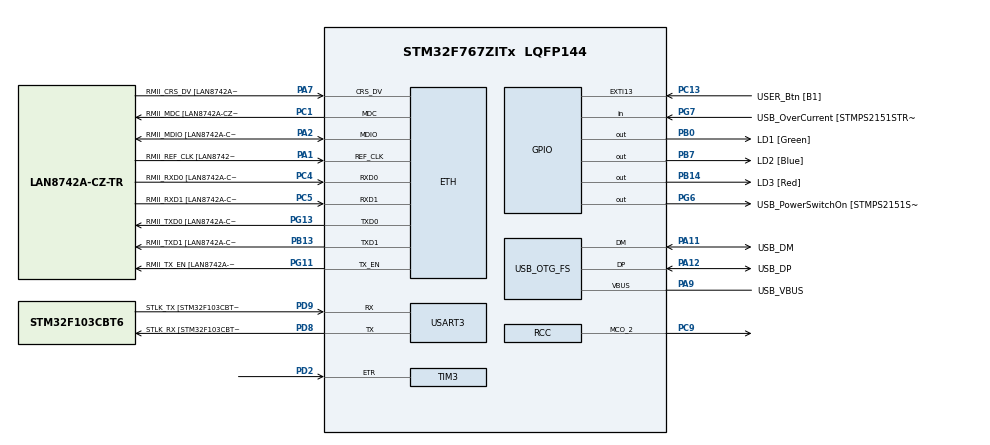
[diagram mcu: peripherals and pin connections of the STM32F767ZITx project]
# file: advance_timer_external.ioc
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ETH.MediaInterface=HAL_ETH_RMII_MODE
ETH.PHY_Name=LAN8742A_PHY_ADDRESS
ETH.PHY_Value=0
ETH.PhyAddress=0
Mcu.Family=STM32F7
Mcu.Name=STM32F767ZITx
Mcu.Package=LQFP144
NVIC.PriorityGroup=NVIC_PRIORITYGROUP_4
PA1.GPIO_Label=RMII_REF_CLK [LAN8742A-CZ-TR_REFCLK0]
PA1.Mode=RMII
PA1.Signal=ETH_REF_CLK
PA10.GPIO_Label=USB_ID
PA10.Signal=USB_OTG_FS_ID
PA11.GPIO_Label=USB_DM
PA11.Mode=Device_Only
PA11.Signal=USB_OTG_FS_DM
PA12.GPIO_Label=USB_DP
PA12.Mode=Device_Only
PA12.Signal=USB_OTG_FS_DP
PA13.GPIO_Label=TMS
PA13.Mode=Serial_Wire
PA13.Signal=SYS_JTMS-SWDIO
PA14.GPIO_Label=TCK
PA14.Mode=Serial_Wire
PA14.Signal=SYS_JTCK-SWCLK
PA2.GPIO_Label=RMII_MDIO [LAN8742A-CZ-TR_MDIO]
PA2.Mode=RMII
PA2.Signal=ETH_MDIO
PA7.GPIO_Label=RMII_CRS_DV [LAN8742A-CZ-TR_CRS_DV]
PA7.Mode=RMII
PA7.Signal=ETH_CRS_DV
PA9.GPIO_Label=USB_VBUS
PA9.Mode=Activate_VBUS
PA9.Signal=USB_OTG_FS_VBUS
PB0.GPIO_Label=LD1 [Green]
PB0.Signal=GPIO_Output
PB13.GPIO_Label=RMII_TXD1 [LAN8742A-CZ-TR_TXD1]
PB13.Mode=RMII
PB13.Signal=ETH_TXD1
PB14.GPIO_Label=LD3 [Red]
PB14.Signal=GPIO_Output
PB3.GPIO_Label=SWO
PB3.Signal=SYS_JTDO-SWO
PB7.GPIO_Label=LD2 [Blue]
PB7.Signal=GPIO_Output
PC1.GPIO_Label=RMII_MDC [LAN8742A-CZ-TR_MDC]
PC1.Mode=RMII
PC1.Signal=ETH_MDC
PC13.GPIO_Label=USER_Btn [B1]
PC13.Signal=GPXTI13
PC14/OSC32_IN.Signal=RCC_OSC32_IN
PC15/OSC32_OUT.Signal=RCC_OSC32_OUT
PC4.GPIO_Label=RMII_RXD0 [LAN8742A-CZ-TR_RXD0]
PC4.Mode=RMII
PC4.Signal=ETH_RXD0
PC5.GPIO_Label=RMII_RXD1 [LAN8742A-CZ-TR_RXD1]
PC5.Mode=RMII
PC5.Signal=ETH_RXD1
PC9.Mode=Clock-out-2
PC9.Signal=RCC_MCO_2
PD2.Signal=S_TIM3_ETR
PD8.GPIO_Label=STLK_RX [STM32F103CBT6_PA3]
PD8.Mode=Asynchronous
PD8.Signal=USART3_TX
PD9.GPIO_Label=STLK_TX [STM32F103CBT6_PA2]
PD9.Mode=Asynchronous
PD9.Signal=USART3_RX
PG11.GPIO_Label=RMII_TX_EN [LAN8742A-CZ-TR_TXEN]
PG11.Mode=RMII
PG11.Signal=ETH_TX_EN
PG13.GPIO_Label=RMII_TXD0 [LAN8742A-CZ-TR_TXD0]
PG13.Mode=RMII
PG13.Signal=ETH_TXD0
PG6.GPIO_Label=USB_PowerSwitchOn [STMPS2151STR_EN]
PG6.Signal=GPIO_Output
PG7.GPIO_Label=USB_OverCurrent [STMPS2151STR_FAULT]
PG7.Signal=GPIO_Input
PH0/OSC_IN.GPIO_Label=MCO [STM32F103CBT6_PA8]
PH0/OSC_IN.Mode=HSE-External-Oscillator
PH0/OSC_IN.Signal=RCC_OSC_IN
PH1/OSC_OUT.Mode=HSE-External-Oscillator
PH1/OSC_OUT.Signal=RCC_OSC_OUT
ProjectManager.HeapSize=0x200
ProjectManager.StackSize=0x400
ProjectManager.TargetToolchain=STM32CubeIDE
RCC.48MHZClocksFreq_Value=24000000
RCC.AHBFreq_Value=216000000
RCC.APB1CLKDivider=RCC_HCLK_DIV4
RCC.APB1Freq_Value=54000000
RCC.APB1TimFreq_Value=108000000
RCC.APB2CLKDivider=RCC_HCLK_DIV2
RCC.APB2Freq_Value=108000000
RCC.APB2TimFreq_Value=216000000
RCC.CortexFreq_Value=216000000
RCC.HCLKFreq_Value=216000000
RCC.HSE_VALUE=8000000
RCC.HSI_VALUE=16000000
RCC.LSE_VALUE=32768
RCC.PLLM=4
RCC.PLLMUL=RCC_PLL_MUL9
RCC.PLLN=216
RCC.PLLQ=9
RCC.PRESCALERUSB=RCC_USBCLKSOURCE_PLL_DIV1_5
RCC.SYSCLKFreq_VALUE=216000000
RCC.SYSCLKSource=RCC_SYSCLKSOURCE_PLLCLK
RCC.SYSCLKSourceVirtual=RCC_SYSCLKSOURCE_PLLCLK
RCC.USBFreq_Value=48000000
RCC.VCOOutputFreq_Value=432000000
SH.S_TIM3_ETR.0=TIM3_ETR,ClockSourceETR_Mode2
USART3.VirtualMode-Asynchronous=VM_ASYNC
USB_OTG_FS.VirtualMode=Device_Only
board=NUCLEO-F767ZI

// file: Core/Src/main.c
/* USER CODE BEGIN Header */
/**
  ******************************************************************************
  * @file           : main.c
  * @brief          : Main program body
  ******************************************************************************
  * @attention
  *
  * Copyright (c) 2026 STMicroelectronics.
  * All rights reserved.
  *
  * This software is licensed under terms that can be found in the LICENSE file
  * in the root directory of this software component.
  * If no LICENSE file comes with this software, it is provided AS-IS.
  *
  ******************************************************************************
  */
/* USER CODE END Header */
#include "main.h"
#include "string.h"

#if defined ( __ICCARM__ ) /*!< IAR Compiler */
#pragma location=0x2007c000
ETH_DMADescTypeDef  DMARxDscrTab[ETH_RX_DESC_CNT]; /* Ethernet Rx DMA Descriptors */
#pragma location=0x2007c0a0
ETH_DMADescTypeDef  DMATxDscrTab[ETH_TX_DESC_CNT]; /* Ethernet Tx DMA Descriptors */

#elif defined ( __CC_ARM )  /* MDK ARM Compiler */

__attribute__((at(0x2007c000))) ETH_DMADescTypeDef  DMARxDscrTab[ETH_RX_DESC_CNT]; /* Ethernet Rx DMA Descriptors */
__attribute__((at(0x2007c0a0))) ETH_DMADescTypeDef  DMATxDscrTab[ETH_TX_DESC_CNT]; /* Ethernet Tx DMA Descriptors */

#elif defined ( __GNUC__ ) /* GNU Compiler */

ETH_DMADescTypeDef DMARxDscrTab[ETH_RX_DESC_CNT] __attribute__((section(".RxDecripSection"))); /* Ethernet Rx DMA Descriptors */
ETH_DMADescTypeDef DMATxDscrTab[ETH_TX_DESC_CNT] __attribute__((section(".TxDecripSection")));   /* Ethernet Tx DMA Descriptors */
#endif

ETH_TxPacketConfig TxConfig;

ETH_HandleTypeDef heth;

TIM_HandleTypeDef htim3;

UART_HandleTypeDef huart3;

PCD_HandleTypeDef hpcd_USB_OTG_FS;

/* USER CODE BEGIN PV */

uint32_t frequency;
uint32_t countervalue1;
uint32_t countervalue2;

/* USER CODE END PV */

void SystemClock_Config(void);
static void MX_GPIO_Init(void);
static void MX_ETH_Init(void);
static void MX_USART3_UART_Init(void);
static void MX_USB_OTG_FS_PCD_Init(void);
static void MX_TIM3_Init(void);

/* USER CODE BEGIN 0 */

/* USER CODE BEGIN 0 */
uint32_t measuer_freq(void)
{
    static uint8_t state = 0;
    static uint32_t start_tick = 0;  // uint32_t yapıldı
    static uint32_t start_count = 0; // uint32_t yapıldı
    uint32_t freq = 0;

    if(state == 0)
    {
        start_tick = HAL_GetTick();
        start_count = __HAL_TIM_GET_COUNTER(&htim3); // __ eklendi
        state = 1;
    }
    else if(state == 1)
    {
        if((HAL_GetTick() - start_tick) >= 1000) // 1 saniye bekle
        {
            uint32_t end_count = __HAL_TIM_GET_COUNTER(&htim3); // __ eklendi

            // Timer taşmasını (overflow) hesaba katan fark alma
            if (end_count >= start_count) {
                freq = end_count - start_count;
                state = 0;
            }

        }
    }
    return freq;
}
/* USER CODE END 0 */

int main(void)
{

  /* MCU Configuration--------------------------------------------------------*/

  /* Reset of all peripherals, Initializes the Flash interface and the Systick. */
  HAL_Init();

  /* Configure the system clock */
  SystemClock_Config();

  /* Initialize all configured peripherals */
  MX_GPIO_Init();
  MX_ETH_Init();
  MX_USART3_UART_Init();
  MX_USB_OTG_FS_PCD_Init();
  MX_TIM3_Init();
  /* USER CODE BEGIN 2 */
  HAL_RCC_MCOConfig(RCC_MCO1, RCC_MCO1SOURCE_HSI, RCC_MCODIV_2);
  HAL_TIM_Base_Start(&htim3);

  /* USER CODE END 2 */

  /* Infinite loop */
  while (1)
  {

    /* USER CODE BEGIN 3 */
	  	 /* external clock mode
	countervalue1 =   __HAL_TIM_GET_COUNTER(&htim3);
	countervalue2 = htim3.Instance->CNT;
	*/

	  /*freqeuncy measure */////

	  frequency = measuer_freq();
  }
  /* USER CODE END 3 */
}

void SystemClock_Config(void)
{
  RCC_OscInitTypeDef RCC_OscInitStruct = {0};
  RCC_ClkInitTypeDef RCC_ClkInitStruct = {0};

  /** Configure the main internal regulator output voltage
  */
  __HAL_RCC_PWR_CLK_ENABLE();
  __HAL_PWR_VOLTAGESCALING_CONFIG(PWR_REGULATOR_VOLTAGE_SCALE3);

  /** Initializes the RCC Oscillators according to the specified parameters
  * in the RCC_OscInitTypeDef structure.
  */
  RCC_OscInitStruct.OscillatorType = RCC_OSCILLATORTYPE_HSI;
  RCC_OscInitStruct.HSIState = RCC_HSI_ON;
  RCC_OscInitStruct.HSICalibrationValue = RCC_HSICALIBRATION_DEFAULT;
  RCC_OscInitStruct.PLL.PLLState = RCC_PLL_ON;
  RCC_OscInitStruct.PLL.PLLSource = RCC_PLLSOURCE_HSI;
  RCC_OscInitStruct.PLL.PLLM = 8;
  RCC_OscInitStruct.PLL.PLLN = 96;
  RCC_OscInitStruct.PLL.PLLP = RCC_PLLP_DIV2;
  RCC_OscInitStruct.PLL.PLLQ = 6;
  RCC_OscInitStruct.PLL.PLLR = 2;
  if (HAL_RCC_OscConfig(&RCC_OscInitStruct) != HAL_OK)
  {
    Error_Handler();
  }

  /** Initializes the CPU, AHB and APB buses clocks
  */
  RCC_ClkInitStruct.ClockType = RCC_CLOCKTYPE_HCLK|RCC_CLOCKTYPE_SYSCLK
                              |RCC_CLOCKTYPE_PCLK1|RCC_CLOCKTYPE_PCLK2;
  RCC_ClkInitStruct.SYSCLKSource = RCC_SYSCLKSOURCE_HSI;
  RCC_ClkInitStruct.AHBCLKDivider = RCC_SYSCLK_DIV1;
  RCC_ClkInitStruct.APB1CLKDivider = RCC_HCLK_DIV2;
  RCC_ClkInitStruct.APB2CLKDivider = RCC_HCLK_DIV1;

  if (HAL_RCC_ClockConfig(&RCC_ClkInitStruct, FLASH_LATENCY_0) != HAL_OK)
  {
    Error_Handler();
  }
  HAL_RCC_MCOConfig(RCC_MCO2, RCC_MCO2SOURCE_SYSCLK, RCC_MCODIV_1);
}

static void MX_ETH_Init(void)
{

   static uint8_t MACAddr[6];

  heth.Instance = ETH;
  MACAddr[0] = 0x00;
  MACAddr[1] = 0x80;
  MACAddr[2] = 0xE1;
  MACAddr[3] = 0x00;
  MACAddr[4] = 0x00;
  MACAddr[5] = 0x00;
  heth.Init.MACAddr = &MACAddr[0];
  heth.Init.MediaInterface = HAL_ETH_RMII_MODE;
  heth.Init.TxDesc = DMATxDscrTab;
  heth.Init.RxDesc = DMARxDscrTab;
  heth.Init.RxBuffLen = 1524;

  if (HAL_ETH_Init(&heth) != HAL_OK)
  {
    Error_Handler();
  }

  memset(&TxConfig, 0 , sizeof(ETH_TxPacketConfig));
  TxConfig.Attributes = ETH_TX_PACKETS_FEATURES_CSUM | ETH_TX_PACKETS_FEATURES_CRCPAD;
  TxConfig.ChecksumCtrl = ETH_CHECKSUM_IPHDR_PAYLOAD_INSERT_PHDR_CALC;
  TxConfig.CRCPadCtrl = ETH_CRC_PAD_INSERT;

}

static void MX_TIM3_Init(void)
{

  TIM_ClockConfigTypeDef sClockSourceConfig = {0};
  TIM_MasterConfigTypeDef sMasterConfig = {0};

  htim3.Instance = TIM3;
  htim3.Init.Prescaler = 0;
  htim3.Init.CounterMode = TIM_COUNTERMODE_UP;
  htim3.Init.Period = 65535;
  htim3.Init.ClockDivision = TIM_CLOCKDIVISION_DIV1;
  htim3.Init.AutoReloadPreload = TIM_AUTORELOAD_PRELOAD_DISABLE;
  if (HAL_TIM_Base_Init(&htim3) != HAL_OK)
  {
    Error_Handler();
  }
  sClockSourceConfig.ClockSource = TIM_CLOCKSOURCE_ETRMODE2;
  sClockSourceConfig.ClockPolarity = TIM_CLOCKPOLARITY_NONINVERTED;
  sClockSourceConfig.ClockPrescaler = TIM_CLOCKPRESCALER_DIV1;
  sClockSourceConfig.ClockFilter = 0;
  if (HAL_TIM_ConfigClockSource(&htim3, &sClockSourceConfig) != HAL_OK)
  {
    Error_Handler();
  }
  sMasterConfig.MasterOutputTrigger = TIM_TRGO_RESET;
  sMasterConfig.MasterSlaveMode = TIM_MASTERSLAVEMODE_DISABLE;
  if (HAL_TIMEx_MasterConfigSynchronization(&htim3, &sMasterConfig) != HAL_OK)
  {
    Error_Handler();
  }

}

static void MX_USART3_UART_Init(void)
{

  huart3.Instance = USART3;
  huart3.Init.BaudRate = 115200;
  huart3.Init.WordLength = UART_WORDLENGTH_8B;
  huart3.Init.StopBits = UART_STOPBITS_1;
  huart3.Init.Parity = UART_PARITY_NONE;
  huart3.Init.Mode = UART_MODE_TX_RX;
  huart3.Init.HwFlowCtl = UART_HWCONTROL_NONE;
  huart3.Init.OverSampling = UART_OVERSAMPLING_16;
  huart3.Init.OneBitSampling = UART_ONE_BIT_SAMPLE_DISABLE;
  huart3.AdvancedInit.AdvFeatureInit = UART_ADVFEATURE_NO_INIT;
  if (HAL_UART_Init(&huart3) != HAL_OK)
  {
    Error_Handler();
  }

}

static void MX_USB_OTG_FS_PCD_Init(void)
{

  hpcd_USB_OTG_FS.Instance = USB_OTG_FS;
  hpcd_USB_OTG_FS.Init.dev_endpoints = 6;
  hpcd_USB_OTG_FS.Init.speed = PCD_SPEED_FULL;
  hpcd_USB_OTG_FS.Init.dma_enable = DISABLE;
  hpcd_USB_OTG_FS.Init.phy_itface = PCD_PHY_EMBEDDED;
  hpcd_USB_OTG_FS.Init.Sof_enable = ENABLE;
  hpcd_USB_OTG_FS.Init.low_power_enable = DISABLE;
  hpcd_USB_OTG_FS.Init.lpm_enable = DISABLE;
  hpcd_USB_OTG_FS.Init.vbus_sensing_enable = ENABLE;
  hpcd_USB_OTG_FS.Init.use_dedicated_ep1 = DISABLE;
  if (HAL_PCD_Init(&hpcd_USB_OTG_FS) != HAL_OK)
  {
    Error_Handler();
  }

}

static void MX_GPIO_Init(void)
{
  GPIO_InitTypeDef GPIO_InitStruct = {0};

  /* GPIO Ports Clock Enable */
  __HAL_RCC_GPIOC_CLK_ENABLE();
  __HAL_RCC_GPIOH_CLK_ENABLE();
  __HAL_RCC_GPIOA_CLK_ENABLE();
  __HAL_RCC_GPIOB_CLK_ENABLE();
  __HAL_RCC_GPIOD_CLK_ENABLE();
  __HAL_RCC_GPIOG_CLK_ENABLE();

  /*Configure GPIO pin Output Level */
  HAL_GPIO_WritePin(GPIOB, LD1_Pin|LD3_Pin|LD2_Pin, GPIO_PIN_RESET);

  /*Configure GPIO pin Output Level */
  HAL_GPIO_WritePin(USB_PowerSwitchOn_GPIO_Port, USB_PowerSwitchOn_Pin, GPIO_PIN_RESET);

  /*Configure GPIO pin : USER_Btn_Pin */
  GPIO_InitStruct.Pin = USER_Btn_Pin;
  GPIO_InitStruct.Mode = GPIO_MODE_IT_RISING;
  GPIO_InitStruct.Pull = GPIO_NOPULL;
  HAL_GPIO_Init(USER_Btn_GPIO_Port, &GPIO_InitStruct);

  /*Configure GPIO pins : LD1_Pin LD3_Pin LD2_Pin */
  GPIO_InitStruct.Pin = LD1_Pin|LD3_Pin|LD2_Pin;
  GPIO_InitStruct.Mode = GPIO_MODE_OUTPUT_PP;
  GPIO_InitStruct.Pull = GPIO_NOPULL;
  GPIO_InitStruct.Speed = GPIO_SPEED_FREQ_LOW;
  HAL_GPIO_Init(GPIOB, &GPIO_InitStruct);

  /*Configure GPIO pin : USB_PowerSwitchOn_Pin */
  GPIO_InitStruct.Pin = USB_PowerSwitchOn_Pin;
  GPIO_InitStruct.Mode = GPIO_MODE_OUTPUT_PP;
  GPIO_InitStruct.Pull = GPIO_NOPULL;
  GPIO_InitStruct.Speed = GPIO_SPEED_FREQ_LOW;
  HAL_GPIO_Init(USB_PowerSwitchOn_GPIO_Port, &GPIO_InitStruct);

  /*Configure GPIO pin : USB_OverCurrent_Pin */
  GPIO_InitStruct.Pin = USB_OverCurrent_Pin;
  GPIO_InitStruct.Mode = GPIO_MODE_INPUT;
  GPIO_InitStruct.Pull = GPIO_NOPULL;
  HAL_GPIO_Init(USB_OverCurrent_GPIO_Port, &GPIO_InitStruct);

  /*Configure GPIO pin : PC9 */
  GPIO_InitStruct.Pin = GPIO_PIN_9;
  GPIO_InitStruct.Mode = GPIO_MODE_AF_PP;
  GPIO_InitStruct.Pull = GPIO_NOPULL;
  GPIO_InitStruct.Speed = GPIO_SPEED_FREQ_LOW;
  GPIO_InitStruct.Alternate = GPIO_AF0_MCO;
  HAL_GPIO_Init(GPIOC, &GPIO_InitStruct);

}

void Error_Handler(void)
{
  __disable_irq();
  while (1)
  {
  }
}
